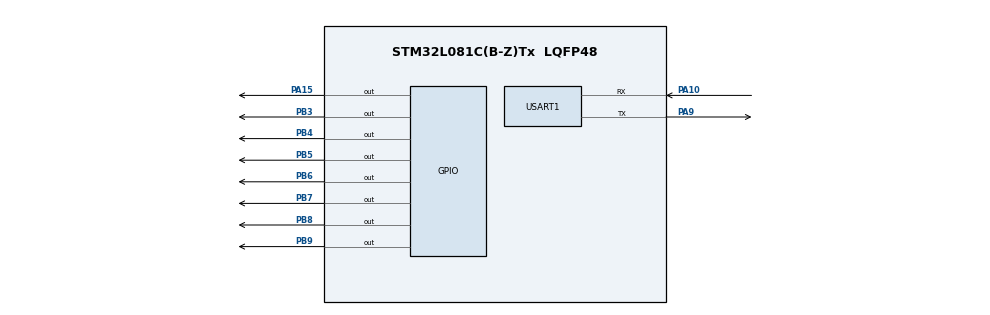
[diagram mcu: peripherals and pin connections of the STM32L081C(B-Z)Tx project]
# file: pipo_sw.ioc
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Mcu.Family=STM32L0
Mcu.Name=STM32L081C(B-Z)Tx
Mcu.Package=LQFP48
PA10.Mode=Asynchronous
PA10.Signal=USART1_RX
PA15.Signal=GPIO_Output
PA9.Mode=Asynchronous
PA9.Signal=USART1_TX
PB3.Signal=GPIO_Output
PB4.Signal=GPIO_Output
PB5.Signal=GPIO_Output
PB6.Signal=GPIO_Output
PB7.Signal=GPIO_Output
PB8.Signal=GPIO_Output
PB9.Signal=GPIO_Output
PH0-OSC_IN.Mode=HSE-External-Oscillator
PH0-OSC_IN.Signal=RCC_OSC_IN
PH1-OSC_OUT.Mode=HSE-External-Oscillator
PH1-OSC_OUT.Signal=RCC_OSC_OUT
ProjectManager.HeapSize=0x200
ProjectManager.StackSize=0x400
ProjectManager.TargetToolchain=SW4STM32
RCC.AHBFreq_Value=8000000
RCC.APB1Freq_Value=8000000
RCC.APB1TimFreq_Value=8000000
RCC.APB2CLKDivider=RCC_HCLK_DIV2
RCC.APB2Freq_Value=4000000
RCC.APB2TimFreq_Value=8000000
RCC.HCLKFreq_Value=8000000
RCC.HSE_VALUE=8000000
RCC.HSI16_VALUE=16000000
RCC.HSI_VALUE=16000000
RCC.LSE_VALUE=32768
RCC.MSI_VALUE=2097000
RCC.PLLDIV=RCC_PLLDIV_3
RCC.PLLSourceVirtual=RCC_PLLSOURCE_HSE
RCC.SYSCLKFreq_VALUE=8000000
RCC.SYSCLKSource=RCC_SYSCLKSOURCE_PLLCLK
RCC.VCOOutputFreq_Value=24000000
USART1.VirtualMode-Asynchronous=VM_ASYNC
USART1.WordLength=WORDLENGTH_8B
VP_AES_VS_AES.Mode=AES_Activate
board=aes_sw

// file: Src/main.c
/**
  ******************************************************************************
  * @file           : main.c
  * @brief          : Main program body
  ******************************************************************************
  ** This notice applies to any and all portions of this file
  * that are not between comment pairs USER CODE BEGIN and
  * USER CODE END. Other portions of this file, whether
  * inserted by the user or by software development tools
  * are owned by their respective copyright owners.
  *
  * COPYRIGHT(c) 2018 STMicroelectronics
  *
  * Redistribution and use in source and binary forms, with or without modification,
  * are permitted provided that the following conditions are met:
  *   1. Redistributions of source code must retain the above copyright notice,
  *      this list of conditions and the following disclaimer.
  *   2. Redistributions in binary form must reproduce the above copyright notice,
  *      this list of conditions and the following disclaimer in the documentation
  *      and/or other materials provided with the distribution.
  *   3. Neither the name of STMicroelectronics nor the names of its contributors
  *      may be used to endorse or promote products derived from this software
  *      without specific prior written permission.
  *
  * THIS SOFTWARE IS PROVIDED BY THE COPYRIGHT HOLDERS AND CONTRIBUTORS "AS IS"
  * AND ANY EXPRESS OR IMPLIED WARRANTIES, INCLUDING, BUT NOT LIMITED TO, THE
  * IMPLIED WARRANTIES OF MERCHANTABILITY AND FITNESS FOR A PARTICULAR PURPOSE ARE
  * DISCLAIMED. IN NO EVENT SHALL THE COPYRIGHT HOLDER OR CONTRIBUTORS BE LIABLE
  * FOR ANY DIRECT, INDIRECT, INCIDENTAL, SPECIAL, EXEMPLARY, OR CONSEQUENTIAL
  * DAMAGES (INCLUDING, BUT NOT LIMITED TO, PROCUREMENT OF SUBSTITUTE GOODS OR
  * SERVICES; LOSS OF USE, DATA, OR PROFITS; OR BUSINESS INTERRUPTION) HOWEVER
  * CAUSED AND ON ANY THEORY OF LIABILITY, WHETHER IN CONTRACT, STRICT LIABILITY,
  * OR TORT (INCLUDING NEGLIGENCE OR OTHERWISE) ARISING IN ANY WAY OUT OF THE USE
  * OF THIS SOFTWARE, EVEN IF ADVISED OF THE POSSIBILITY OF SUCH DAMAGE.
  *
  ******************************************************************************
  */
#include "main.h"
#include "stm32l0xx_hal.h"

UART_HandleTypeDef huart1;

/* USER CODE BEGIN PV */
/* Private variables ---------------------------------------------------------*/

__ALIGN_BEGIN static uint64_t k1 __ALIGN_END = 0x6DC416DD779428D2;
__ALIGN_BEGIN static uint64_t k0 __ALIGN_END = 0x7E1D20AD2E152297;

__ALIGN_BEGIN static uint8_t m[10] __ALIGN_END = {
                            0x00,0x00,0x00,0x00,0x00,0x00,0x00,0x00,0x00,0x00};

__ALIGN_BEGIN static uint8_t X[8] __ALIGN_END = {
                            0x26,0x00,0x27,0x1E,0xF6,0x52,0x85,0x09};

/* USER CODE END PV */

void SystemClock_Config(void);
static void MX_GPIO_Init(void);
static void MX_USART1_UART_Init(void);

void setMask();

/* USER CODE BEGIN PFP */
/* Private function prototypes -----------------------------------------------*/

/* USER CODE END PFP */

/* USER CODE BEGIN 0 */
extern void nops ();
extern void rlayer (uint8_t *X);
extern void slayer (uint8_t *X, uint8_t *m, uint8_t *T, uint8_t c);
/* USER CODE END 0 */

int main(void)
{
	HAL_Init();

	SystemClock_Config();

	MX_GPIO_Init();
	MX_USART1_UART_Init();

	while (1)
	{
		uint8_t command = 0;
		HAL_StatusTypeDef stat = HAL_UART_Receive(&huart1, &command, 1, HAL_MAX_DELAY);
		if (stat == HAL_OK)
		{
			switch(command)
			{
			case 0x01:
				setMask();
				//stat = HAL_UART_Receive(&huart1, m, 10, HAL_MAX_DELAY);
				//stat = HAL_UART_Transmit(&huart1, m, 10, HAL_MAX_DELAY);
				break;

			case 0x02:
				stat = HAL_UART_Receive(&huart1, X, 8, HAL_MAX_DELAY);

					uint32_t st_temp = SysTick->CTRL;
					SysTick->CTRL = 0;

					nops();

					//trigger high
					GPIOA->BSRR = GPIO_PIN_15;

				//******************************************************************//
					// PIPO cipher until 1. Round out to test results of board
					// Preparation of Slayer
					uint8_t T[3] = {0};
					uint8_t c = (m[0] | m[1]);

					uint8_t *round_key = (uint8_t *)&k0;
					// XOR masked Whitening Key
					X[0] ^= round_key[0] ^ m[2];
					X[1] ^= round_key[1] ^ m[2];
					X[2] ^= round_key[2] ^ m[2];
					X[3] ^= round_key[3] ^ m[1];
					X[4] ^= round_key[4] ^ m[2];
					X[5] ^= round_key[5] ^ m[2];
					X[6] ^= round_key[6] ^ m[2];
					X[7] ^= round_key[7] ^ m[2];

				// Round 1
					// S-Boxes
					slayer(X, m, T, c);

					// R-Layer
					rlayer(X);

					// Add Round Key XOR round constant
					round_key = (uint8_t *)&k1;
					X[0] ^= round_key[0] ^ m[1] ^ 1;
					for (int j = 1; j < 8; j++) {
						X[j] ^= round_key[j] ^ m[j + 2];
					}

				//******************************************************************//

					//trigger low
					GPIOA->BRR = GPIO_PIN_15;

					SysTick->CTRL = st_temp;

					stat = HAL_UART_Transmit(&huart1, X, 8, HAL_MAX_DELAY);
				break;

			default:
				HAL_UART_Transmit(&huart1, &command, 1, HAL_MAX_DELAY);
			}
		}
	}

}

void setMask()
{
	HAL_StatusTypeDef stat = HAL_UART_Receive(&huart1, m, 10, HAL_MAX_DELAY);

	stat = HAL_UART_Transmit(&huart1, m, 10, HAL_MAX_DELAY);
}

//void SystemClock_Config(void)
//{
//
//  RCC_OscInitTypeDef RCC_OscInitStruct;
//  RCC_ClkInitTypeDef RCC_ClkInitStruct;
//  RCC_PeriphCLKInitTypeDef PeriphClkInit;
//
//    /**Configure the main internal regulator output voltage
//    */
//  __HAL_PWR_VOLTAGESCALING_CONFIG(PWR_REGULATOR_VOLTAGE_SCALE1);
//
//    /**Initializes the CPU, AHB and APB busses clocks
//    */
//  RCC_OscInitStruct.OscillatorType = RCC_OSCILLATORTYPE_HSE;
//  RCC_OscInitStruct.HSEState = RCC_HSE_ON;
//  RCC_OscInitStruct.PLL.PLLState = RCC_PLL_ON;
//  RCC_OscInitStruct.PLL.PLLSource = RCC_PLLSOURCE_HSE;
//  RCC_OscInitStruct.PLL.PLLMUL = RCC_PLLMUL_3;
//  RCC_OscInitStruct.PLL.PLLDIV = RCC_PLLDIV_3;
//  if (HAL_RCC_OscConfig(&RCC_OscInitStruct) != HAL_OK)
//  {
//    _Error_Handler(__FILE__, __LINE__);
//  }
//
//    /**Initializes the CPU, AHB and APB busses clocks
//    */
//  RCC_ClkInitStruct.ClockType = RCC_CLOCKTYPE_HCLK|RCC_CLOCKTYPE_SYSCLK
//                              |RCC_CLOCKTYPE_PCLK1|RCC_CLOCKTYPE_PCLK2;
//  RCC_ClkInitStruct.SYSCLKSource = RCC_SYSCLKSOURCE_PLLCLK;
//  RCC_ClkInitStruct.AHBCLKDivider = RCC_SYSCLK_DIV1;
//  RCC_ClkInitStruct.APB1CLKDivider = RCC_HCLK_DIV1;
//  RCC_ClkInitStruct.APB2CLKDivider = RCC_HCLK_DIV2;
//
//  if (HAL_RCC_ClockConfig(&RCC_ClkInitStruct, FLASH_LATENCY_0) != HAL_OK)
//  {
//    _Error_Handler(__FILE__, __LINE__);
//  }
//
//  PeriphClkInit.PeriphClockSelection = RCC_PERIPHCLK_USART1;
//  PeriphClkInit.Usart1ClockSelection = RCC_USART1CLKSOURCE_PCLK2;
//  if (HAL_RCCEx_PeriphCLKConfig(&PeriphClkInit) != HAL_OK)
//  {
//    _Error_Handler(__FILE__, __LINE__);
//  }
//
//    /**Configure the Systick interrupt time
//    */
//  HAL_SYSTICK_Config(HAL_RCC_GetHCLKFreq()/1000);
//
//    /**Configure the Systick
//    */
//  HAL_SYSTICK_CLKSourceConfig(SYSTICK_CLKSOURCE_HCLK);
//
//  /* SysTick_IRQn interrupt configuration */
//  HAL_NVIC_SetPriority(SysTick_IRQn, 0, 0);
//}

void SystemClock_Config(void)
{

  RCC_OscInitTypeDef RCC_OscInitStruct;
  RCC_ClkInitTypeDef RCC_ClkInitStruct;

    //Configure the main internal regulator output voltage

  __HAL_PWR_VOLTAGESCALING_CONFIG(PWR_REGULATOR_VOLTAGE_SCALE1);

    //Initializes the CPU, AHB and APB busses clocks

  RCC_OscInitStruct.OscillatorType = RCC_OSCILLATORTYPE_HSE;
  RCC_OscInitStruct.HSEState = RCC_HSE_ON;
  //RCC_OscInitStruct.HSEState = RCC_HSE_BYPASS;
  RCC_OscInitStruct.PLL.PLLState = RCC_PLL_NONE;
  if (HAL_RCC_OscConfig(&RCC_OscInitStruct) != HAL_OK)
  {
    _Error_Handler(__FILE__, __LINE__);
  }

    //Initializes the CPU, AHB and APB busses clocks

  RCC_ClkInitStruct.ClockType = RCC_CLOCKTYPE_HCLK|RCC_CLOCKTYPE_SYSCLK
                              |RCC_CLOCKTYPE_PCLK1|RCC_CLOCKTYPE_PCLK2;
  RCC_ClkInitStruct.SYSCLKSource = RCC_SYSCLKSOURCE_HSE;
  RCC_ClkInitStruct.AHBCLKDivider = RCC_SYSCLK_DIV1;
  RCC_ClkInitStruct.APB1CLKDivider = RCC_HCLK_DIV1;
  RCC_ClkInitStruct.APB2CLKDivider = RCC_HCLK_DIV1;

  if (HAL_RCC_ClockConfig(&RCC_ClkInitStruct, FLASH_LATENCY_0) != HAL_OK)
  {
    _Error_Handler(__FILE__, __LINE__);
  }

    //Configure the Systick interrupt time

  HAL_SYSTICK_Config(HAL_RCC_GetHCLKFreq()/1000);

    //Configure the Systick

  HAL_SYSTICK_CLKSourceConfig(SYSTICK_CLKSOURCE_HCLK);

  // SysTick_IRQn interrupt configuration
  HAL_NVIC_SetPriority(SysTick_IRQn, 0, 0);
}

/* USART1 init function */
static void MX_USART1_UART_Init(void)
{

  huart1.Instance = USART1;
  huart1.Init.BaudRate = 115200;
  huart1.Init.WordLength = UART_WORDLENGTH_8B;
  huart1.Init.StopBits = UART_STOPBITS_1;
  huart1.Init.Parity = UART_PARITY_NONE;
  huart1.Init.Mode = UART_MODE_TX_RX;
  huart1.Init.HwFlowCtl = UART_HWCONTROL_NONE;
  huart1.Init.OverSampling = UART_OVERSAMPLING_16;
  huart1.Init.OneBitSampling = UART_ONE_BIT_SAMPLE_DISABLE;
  huart1.AdvancedInit.AdvFeatureInit = UART_ADVFEATURE_NO_INIT;
  if (HAL_UART_Init(&huart1) != HAL_OK)
  {
    _Error_Handler(__FILE__, __LINE__);
  }

}

/** Configure pins as
        * Analog
        * Input
        * Output
        * EVENT_OUT
        * EXTI
*/
static void MX_GPIO_Init(void)
{

  GPIO_InitTypeDef GPIO_InitStruct;

  /* GPIO Ports Clock Enable */
  __HAL_RCC_GPIOH_CLK_ENABLE();
  __HAL_RCC_GPIOA_CLK_ENABLE();
  __HAL_RCC_GPIOB_CLK_ENABLE();

  /*Configure GPIO pin Output Level */
  HAL_GPIO_WritePin(GPIOA, GPIO_PIN_15, GPIO_PIN_RESET);

  /*Configure GPIO pin Output Level */
  HAL_GPIO_WritePin(GPIOB, GPIO_PIN_3|GPIO_PIN_4|GPIO_PIN_5|GPIO_PIN_6
                          |GPIO_PIN_7|GPIO_PIN_8|GPIO_PIN_9, GPIO_PIN_RESET);

  /*Configure GPIO pin : PA15 */
  GPIO_InitStruct.Pin = GPIO_PIN_15;
  GPIO_InitStruct.Mode = GPIO_MODE_OUTPUT_PP;
  GPIO_InitStruct.Pull = GPIO_NOPULL;
  GPIO_InitStruct.Speed = GPIO_SPEED_FREQ_LOW;
  HAL_GPIO_Init(GPIOA, &GPIO_InitStruct);

  /*Configure GPIO pins : PB3 PB4 PB5 PB6
                           PB7 PB8 PB9 */
  GPIO_InitStruct.Pin = GPIO_PIN_3|GPIO_PIN_4|GPIO_PIN_5|GPIO_PIN_6
                          |GPIO_PIN_7|GPIO_PIN_8|GPIO_PIN_9;
  GPIO_InitStruct.Mode = GPIO_MODE_OUTPUT_PP;
  GPIO_InitStruct.Pull = GPIO_NOPULL;
  GPIO_InitStruct.Speed = GPIO_SPEED_FREQ_LOW;
  HAL_GPIO_Init(GPIOB, &GPIO_InitStruct);

}

void _Error_Handler(char *file, int line)
{
  while(1)
  {
  }
}

/************************ (C) COPYRIGHT STMicroelectronics *****END OF FILE****/
